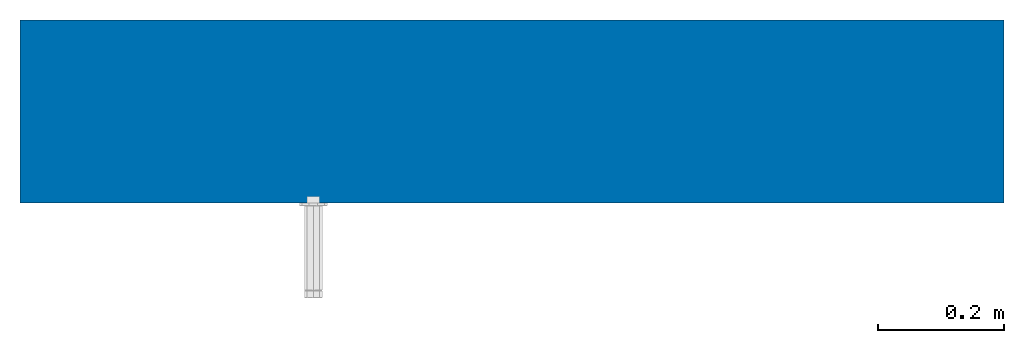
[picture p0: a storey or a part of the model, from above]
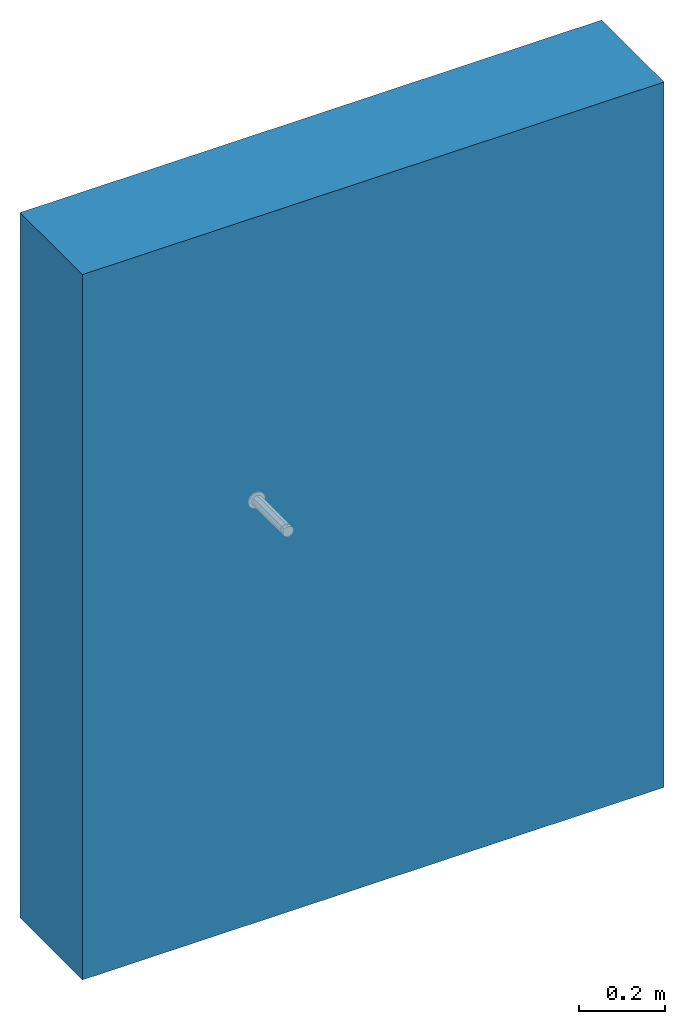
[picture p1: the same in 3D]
Properties of the parts of a building model (IFC2X3)

# File
Description: ViewDefinition [CoordinationView]
File name: Project Number
Time: 2019-10-03T16:50:53
Written by: The EXPRESS Data Manager Version 5.02.0100.07 : 28 Aug 2013
Made in: 20151007_0715(x64) - Exporter 16.0.1063.0 - Default UI
Comment: STEP Physical File produced by: The EXPRESS Data Manager Version 5.02.0100.07 : 28 Aug 2013 * Module: EDMstepFileFactory/EDMstandAlone * Creation date: Thu Oct 03 16:50:53 2019 * Host: SarahSams-HP * Database: C:\Users\SARAHS~1\AppData\Local\Temp\{4140D4EA-D61A-4CEE-9009-91222229488A}\ifc * Database version: 5507 * Database creation date: Thu Oct 03 16:50:51 2019 * Schema: IFC2X3 * Model: DataRepository.ifc * Model creation date: Thu Oct 03 16:50:52 2019 * Header model: DataRepository.ifc_HeaderModel * Header model creation date: Thu Oct 03 16:50:52 2019 * EDMuser: sdai-user * EDMgroup: sdai-group * License ID and type: 5605 : Permanent license. Expiry date: * EDMstepFileFactory options: 020000

# IfcProject, Project Number
LongName: Project Name; Phase: Project Status

# IfcSite, Default
RefLatitude: 51, 30, 23, 112487; RefLongitude: 0, -7, -37, -956022; RefElevation: 0 mm
Other - Category: Project Information; Client Name: Owner; Project Address: Enter address here; Project Issue Date: Issue Date; Project Name: Project Name; Project Number: Project Number; Project Status: Project Status

# IfcBuilding
Pset_BuildingCommon - NumberOfStoreys: 1
Other - Category: Project Information; Client Name: Owner; Project Address: Enter address here; Project Issue Date: Issue Date; Project Name: Project Name; Project Number: Project Number; Project Status: Project Status

# IfcBuildingStorey, Level 0
LongName: Level 0; Elevation: 0 mm
Other - Category: Levels; Family Name: Level; Family: Level: Circle Head - Project Datum; Family and Type: Level: Circle Head - Project Datum; Type: Level: Circle Head - Project Datum; Type Id: Level: Circle Head - Project Datum
Identity Data - Type Name: Circle Head - Project Datum; Structural: no; Building Story: yes; Name: Level 0
Constraints - Elevation: 0 mm; Elevation Base: Project Base Point
Dimensions - Computation Height: 0 mm
Graphics - Color: 0; Line Pattern: Centre; Line Weight: 1; Symbol: Anno_Level_Head_Circle: Standard; Symbol at End 1 Default: yes; Symbol at End 2 Default: no

# IfcBuildingElementProxy: Transformer Brushed Stainless Steel, Duten_SoapDpnsrs_S260:Transformer Brushed Stainless Steel:298036
In: Level 0
Type - PredefinedType: USERDEFINED; Classification: E2020200 Furniture & Accessories (Uniformat); Material: Duten_Metal_BrushedStainlessSteel, Duten_Plastic_Black
Type - Constraints - Default Elevation: 1200 mm
Type - General - Author: Diane Butterworth Ltd; ManufacturerName: Duten; ManufacturerURL: http://www.duten.fr/; NBSDescription: Soap dispensers; NBSReference: 45-35-72/358; ProductInformation: https://www.duten.co.uk/products/soap-dispensers/touch-free-soap-dispenser-s260; Revision: n/a; Uniclass2015Code: Pr_40_70_22_81; Uniclass2015Title: Soap dispensers; Uniclass2015Version: Pr-Products v1.10
Type - Graphics - Include MF Pump: no
Type - Identity Data - Assembly Code: E2020200; Assembly Description: Furniture & Accessories; Cost: 0; Description: Transformer Brished Stainless Steel; Keynote: Pr_40_70_22_81; Manufacturer: Duten; Model: S260-S_SEC; Type Comments: Transformer Brished Stainless Steel; Type Name: Transformer Brushed Stainless Steel; URL: http://www.duten.fr/
Type - Materials and Finishes - DispenserFinish: Duten_Metal_BrushedStainlessSteel; SensorFinish: Duten_Plastic_Black
Type - Mechanical - CWFU: 0; HWFU: 0; WFU: 0
Type - Other - AccessibilityPerformance: n/a; AssetIdentifier: n/a; AssetType: Moveable; BarCode: n/a; Category: n/a; CodePerformance: Pr_40_70_22_81: Soap dispensers; Color: Defined by Finish; Constituents: Stainless Steel Dispenser, Transformer or Battery; DurationUnit: Years; ExpectedLife: 5; Family Name: Duten_SoapDpnsrs_S260; Features: Electronic counter mounted touch-free sensor soap dispenser. Battery or mains powered. Accepts all types of liquid soap, except microbeads. Anti-drip valve distribution system.; Finish: Available in Brushed, Polished or Matte Black Stainless Steel; Grade: n/a; InstallationDate: 1900-12-31T23:59:59; Material: Stainless Steel; ModelNumber: S260-S_SEC; ModelReference: Transformer Brished Stainless Steel; Name: SoapDispensers_S260_Duten; ReplacementCost: 0; SerialNumber: n/a; Shape: Rectangular; Size: (H) 150mm x (L) 28mm x (W) 28mm; SustainabilityPerformance: n/a; TagNumber: n/a; WarrantyDescription: n/a; WarrantyDurationLabor: 5; WarrantyDurationParts: 5; WarrantyDurationUnit: Years; WarrantyGuarantorLabor: contact@duten.fr; WarrantyGuarantorParts: contact@duten.fr; WarrantyStartDate: 1900-12-31T23:59:59
Type - Plumbing - CW Connection: no; HW Connection: no; Vent Connection: no; Waste Connection: no
Pset_BuildingElementProxyCommon - Reference: n/a
Pset_ManufacturerTypeInformation - ModelReference: Transformer Brished Stainless Steel; Manufacturer: Duten
Constraints - Elevation: 1200 mm; Host: Basic Wall : Wall-Ext_102Bwk-75Ins-100LBlk-12P; Level: Level: Level 0
Dimensions - Area: 0.0271762 m2; Volume: 0.000296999 m3
Other - Category: Generic Models; Family: Duten_SoapDpnsrs_S260: Transformer Brushed Stainless Steel; Family and Type: Duten_SoapDpnsrs_S260: Transformer Brushed Stainless Steel; Schedule Level: Level: Level 0; Type: Duten_SoapDpnsrs_S260: Transformer Brushed Stainless Steel; Type Id: Duten_SoapDpnsrs_S260: Transformer Brushed Stainless Steel
Phasing - Phase Created: New Construction

# IfcWallStandardCase: Basic Wall:Wall-Ext_102Bwk-75Ins-100LBlk-12P, Basic Wall:Wall-Ext_102Bwk-75Ins-100LBlk-12P:294806
In: Level 0
Type - PredefinedType: STANDARD; Material: Brick, Common 102.5 mm, Fiberglass Batt 75 mm, Concrete Masonry Units _Low Density 100 mm, Plaster 12.5 mm
Type - Analytical Properties - Absorptance: 0.7; Heat Transfer Coefficient (U): 0.235926; Roughness: 3; Thermal mass: 300303; Thermal Resistance (R): 4.23862
Type - Construction - Function: Exterior; Width: 290 mm; Wrapping at Inserts: Both
Type - Graphics - Coarse Scale Fill Color: 12632256; Coarse Scale Fill Pattern: Solid fill
Type - Identity Data - Keynote: F10; Type Name: Wall-Ext_102Bwk-75Ins-100LBlk-12P
Type - Materials and Finishes - Structural Material: Concrete Masonry Units _Low Density
Type - Other - Category: Walls; Family Name: Basic Wall
Constraints - Base Constraint: Level: Level 0; Base Extension Distance: 0 mm; Base is Attached: no; Base Offset: 0 mm; Location Line: Wall Centerline; Related to Mass: no; Room Bounding: yes; Top Extension Distance: 0 mm; Top is Attached: no; Top Offset: 0 mm; Unconnected Height: 2000 mm
Dimensions - Area: 3.12 m2; Length: 1560 mm; Volume: 0.9048 m3
Other - Family: Basic Wall: Wall-Ext_102Bwk-75Ins-100LBlk-12P; Family and Type: Basic Wall: Wall-Ext_102Bwk-75Ins-100LBlk-12P; Type: Basic Wall: Wall-Ext_102Bwk-75Ins-100LBlk-12P; Type Id: Basic Wall: Wall-Ext_102Bwk-75Ins-100LBlk-12P
Phasing - Phase Created: New Construction
Structural - Enable Analytical Model: no; Structural: no; Structural Usage: Non-bearing
Pset_WallCommon - Reference: Wall-Ext_102Bwk-75Ins-100LBlk-12P; LoadBearing: no; ExtendToStructure: no; IsExternal: yes; ThermalTransmittance: 0.235926 kg/K/s3
